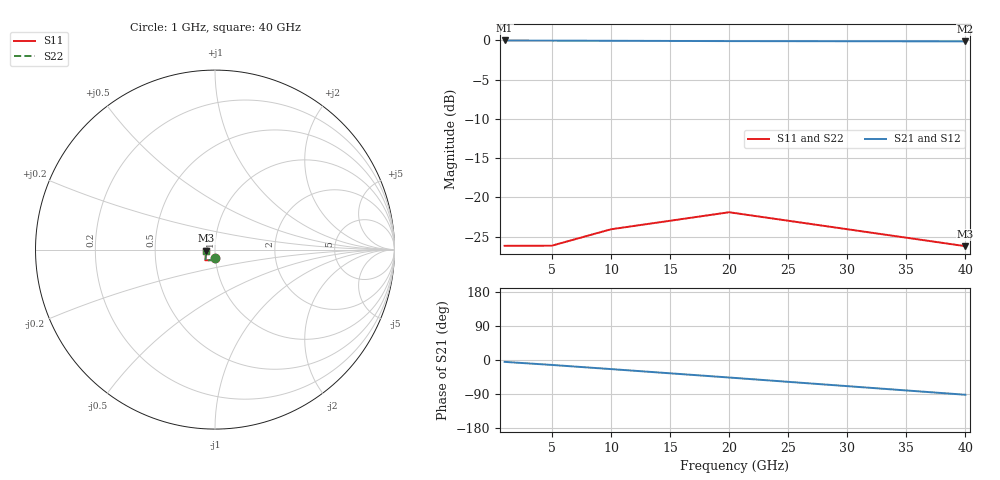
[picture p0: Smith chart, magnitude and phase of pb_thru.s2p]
! Generated by circuitRF - EM: Palace
! circuitRF-EM setup: g_thru_solids
! circuitRF-EM layout: thru/layout/thru.clay
! circuitRF-EM written: 2026-11-04 23:59:55Z
! circuitRF-EM geometry: 21c4f49c464207e4
! circuitRF-EM mesh: be36879526fbbc1a
! circuitRF-EM ports: 1a591d5b5a03db7b
! circuitRF-EM model: Palace 0.18.1 (0dc74cd, schema 1-7-0)
! Port[1] = port/1
! Port[2] = port/2
! circuitRF-EM port 1: 'port/1' from 'airbox/zmin' to 'Metal1/1', wave (mode 1), 50 Ohm: Palace's S is referred to the mode's own impedance Z_PV, renormalised here to 50 Ohm; reference plane 0 um into the structure from the port face
! circuitRF-EM port 2: 'port/2' from 'airbox/zmin' to 'Metal1/1', wave (mode 1), 50 Ohm: Palace's S is referred to the mode's own impedance Z_PV, renormalised here to 50 Ohm; reference plane 0 um into the structure from the port face
! circuitRF-EM 3D mesh: 14,830 elements initially, 14,830 finally, 0 adaptive pass(es), element order 2
! circuitRF-EM 3D operating temperature: 20 C
! circuitRF-EM 3D run: preset Standard; 14830 -> 14830 tetrahedra; 102812 unknowns; 0 refinement pass(es); 6 frequency sample(s)
! circuitRF-EM 3D run cost: wall 881 s; Palace peak memory 1.7 GB
! circuitRF-EM 3D DC row: circuitRF conduction solve of the conductors, 4,203 elements, 0.19 s; ports as terminal pairs
! circuitRF-EM: re-running the EM setup rewrites this file. If circuitRF reports it as stale, the layout's cross-section changed after this file was written.
# GHz S RI R 50
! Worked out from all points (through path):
!   5 points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, 1 GHz to 40 GHz, reference 50 ohm
!   highest |S21| = -0.01 dB at 1 GHz (marker M1); lowest = -0.1 dB at 40 GHz (marker M2)
!   lowest |S11| = -26.2 dB at 40 GHz (marker M3), VSWR 1.10, Z = 45.4 - j0.552 ohm
!   |S11| at or under -10 dB: start of sweep to end of sweep
!   |S22| runs from -26.2 to -21.9 dB; largest |S21 - S12| = 7.3e-05
1  -0.00244 -0.049  0.9952 -0.0856  0.9952 -0.0856  -0.00244 -0.049
5  -0.00836 -0.0485  0.9709 -0.2248  0.9709 -0.2248  -0.00835 -0.0485
10  -0.0216 -0.0587  0.9081 -0.4042  0.9081 -0.4042  -0.0216 -0.0587
20  -0.0535 -0.0599  0.6846 -0.7144  0.6846 -0.7144  -0.0534 -0.0601
40  -0.0485 -0.00607  -0.0298 -0.9853  -0.0297 -0.9853  -0.0486 -0.00728
